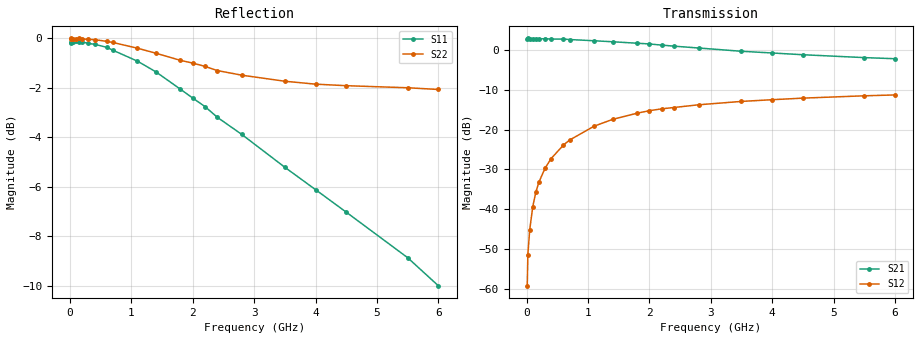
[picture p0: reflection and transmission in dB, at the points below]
! SIEMENS Discrete & RF Semiconductors
! BFY180
! Si NPN RF Bipolar Junction Transistor in MICRO-X
! VCE = 1 V  IC = 0.4 mA
! Common Emitter S-Parameters:  May  1997
# GHz  S  MA  R  50
!  f  S11  S21  S12  S22
! GHz  MAG  ANG  MAG  ANG  MAG  ANG  MAG  ANG
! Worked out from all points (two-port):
!   36 points, 10 MHz to 6 GHz, reference 50 ohm
!   highest |S21| = 2.87 dB at 20 MHz (marker M1); lowest = -2.2 dB at 6 GHz (marker M2)
!   |S21| within 3 dB of the highest: start of sweep to 3.273 GHz
!   lowest |S11| = -10.0 dB at 6 GHz (marker M3), VSWR 1.92, Z = 28.9 - j14 ohm
!   |S11| at or under -10 dB: 5.997242 GHz to end of sweep
!   |S22| runs from -2.1 to 0.0 dB; largest |S21 - S12| = 1.4
!   S11 on the Smith chart (normalised r, x): 10 MHz: open; 700 MHz: 0.69, -4.84; 1.4 GHz: 0.53, -2.37; 2.4 GHz: 0.51, -1.29; 4 GHz: 0.53, -0.68; 6 GHz: 0.58, -0.28
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0.01  0.9833 -0.2  1.373 179.9  0.0011 83.3  0.9987 -0.3
0.02  0.9763 -0.3  1.391 179.4  0.0027 94.8  0.9999 -0.5
0.05  0.9853 -1.5  1.369 178.1  0.0055 84.6  0.9985 -1.2
0.1  0.9869 -3.3  1.385 176.0  0.0108 89.1  0.9955 -2.3
0.15  0.9834 -5.0  1.37 173.8  0.0164 86.4  0.9995 -3.5
0.2  0.9831 -6.6  1.363 171.6  0.0219 84.5  0.9972 -4.7
0.3  0.9765 -9.7  1.382 167.2  0.0327 82.3  0.9951 -6.9
0.4  0.9729 -13.0  1.361 163.1  0.0433 79.7  0.9939 -9.2
0.6  0.959 -19.5  1.363 154.0  0.0639 74.4  0.9861 -13.8
0.7  0.9461 -22.9  1.345 150.7  0.0738 71.4  0.9809 -16.0
1.1  0.8991 -34.8  1.298 134.8  0.1102 61.7  0.9551 -24.7
1.4  0.8555 -44.1  1.261 123.5  0.134 54.6  0.9331 -31.0
1.8  0.7889 -55.3  1.209 108.6  0.1603 46.8  0.9025 -38.4
2  0.7571 -60.5  1.184 101.4  0.1723 42.9  0.8912 -42.0
2.2  0.7277 -65.3  1.145 94.9  0.1817 39.1  0.8775 -45.5
2.4  0.6924 -70.4  1.111 88.6  0.1889 35.9  0.8607 -48.7
2.8  0.6391 -78.7  1.053 77.2  0.2043 30.2  0.8423 -54.6
3.5  0.5486 -91.6  0.958 58.6  0.2252 21.6  0.8189 -64.4
4  0.4943 -100.5  0.912 47.3  0.2366 15.8  0.8079 -71.2
4.5  0.4451 -108.8  0.867 36.8  0.2476 10.6  0.8021 -78.1
5.5  0.3601 -126.0  0.798 17.4  0.2648 0.5  0.7944 -92.3
6  0.316 -136.4  0.773 8.8  0.2715 -4.6  0.7881 -99.4
